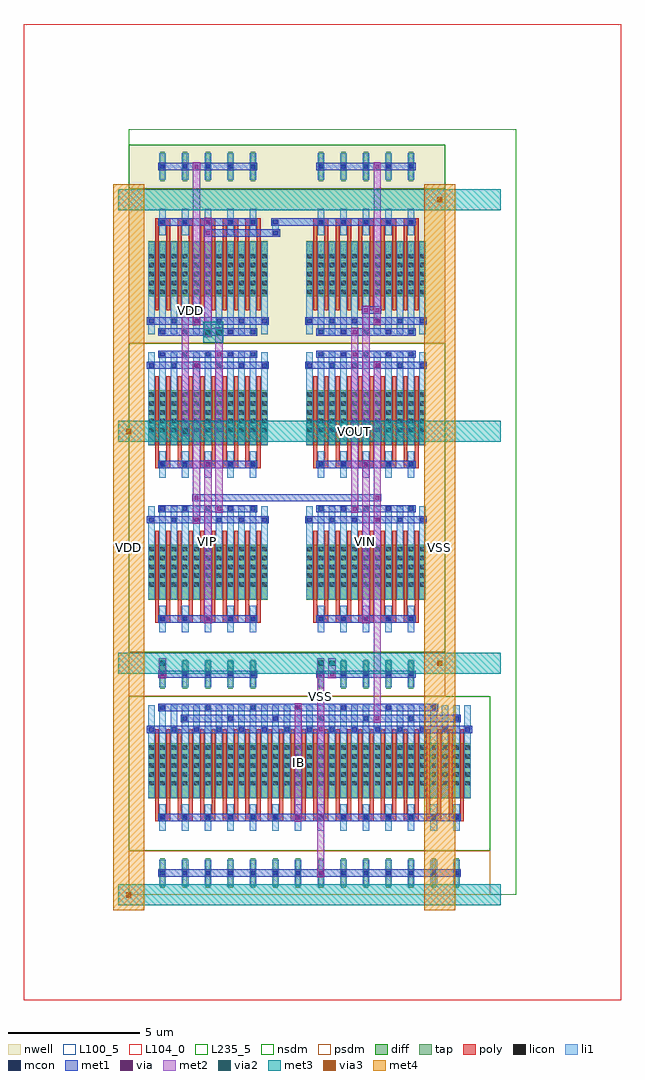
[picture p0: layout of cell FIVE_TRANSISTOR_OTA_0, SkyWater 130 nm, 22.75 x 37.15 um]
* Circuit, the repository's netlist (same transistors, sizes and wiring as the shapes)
* NGSPICE file created from FIVE_TRANSISTOR_OTA_0.ext - technology: sky130A

.subckt DCL_PMOS_S_78259359_X5_Y1_1774868955 a_200_252# w_0_0#
X0 a_200_252# a_200_252# w_0_0# w_0_0# sky130_fd_pr__pfet_01v8 ad=0.294 pd=2.38 as=0.5565 ps=4.73 w=2.1 l=0.15 M=10
.ends

.subckt NMOS_4T_1818045_X5_Y2_1774868956 a_230_357# a_200_252# a_147_357# a_241_2408#
X0 a_230_357# a_200_252# a_147_357# a_241_2408# sky130_fd_pr__nfet_01v8 ad=0.294 pd=2.38 as=0.294 ps=2.38 w=2.1 l=0.15 M=20
.ends

.subckt PMOS_S_49267959_X5_Y1_1774868957 a_230_357# a_200_252# w_0_0#
X0 a_230_357# a_200_252# w_0_0# w_0_0# sky130_fd_pr__pfet_01v8 ad=0.294 pd=2.38 as=0.5565 ps=4.73 w=2.1 l=0.15 M=10
.ends

.subckt SCM_NMOS_72619132_X7_Y1_1774868958 a_200_252# a_402_357# a_147_357#
X0 a_200_252# a_200_252# a_147_357# a_147_357# sky130_fd_pr__nfet_01v8 ad=0.294 pd=2.38 as=0.294 ps=2.38 w=2.1 l=0.15 M=14
X1 a_147_357# a_200_252# a_402_357# a_147_357# sky130_fd_pr__nfet_01v8 ad=0.294 pd=2.38 as=0.294 ps=2.38 w=2.1 l=0.15 M=14
.ends

.subckt FIVE_TRANSISTOR_OTA_0 IB VOUT VIP VIN VSS VDD
XDCL_PMOS_S_78259359_X5_Y1_1774868955_0 m2_574_4247# VDD DCL_PMOS_S_78259359_X5_Y1_1774868955
XNMOS_4T_1818045_X5_Y2_1774868956_0 VOUT VIN m1_484_2996# VSS NMOS_4T_1818045_X5_Y2_1774868956
XNMOS_4T_1818045_X5_Y2_1774868956_1 m2_574_4247# VIP m1_484_2996# VSS NMOS_4T_1818045_X5_Y2_1774868956
XPMOS_S_49267959_X5_Y1_1774868957_0 VOUT m2_574_4247# VDD PMOS_S_49267959_X5_Y1_1774868957
XSCM_NMOS_72619132_X7_Y1_1774868958_0 IB m1_484_2996# VSS SCM_NMOS_72619132_X7_Y1_1774868958
.ends

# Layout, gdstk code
from math import pi, radians
import gdstk
lib = gdstk.Library(unit=1e-6, precision=1e-09)
def R(c, l, rs):  # rectangles x0, y0, x1, y1
    for r in rs: c.add(gdstk.rectangle(r[:2], r[2:], *l))
def A(c, l, x, y, w, h, nx, ny, dx, dy):  # array of equal rectangles
    R(c, l, [(x+i*dx, y+j*dy, x+i*dx+w, y+j*dy+h) for i in range(nx) for j in range(ny)])
def P(c, l, *ps):  # polygons
    for p in ps: c.add(gdstk.Polygon(p, *l))
nwell = (64, 20)
diff = (65, 20)
tap = (65, 44)
poly = (66, 20)
licon = (66, 44)
li1 = (67, 20)
mcon = (67, 44)
met1 = (68, 20)
via = (68, 44)
met2 = (69, 20)
via2 = (69, 44)
met3 = (70, 20)
via3 = (70, 44)
met4 = (71, 20)
nsdm = (93, 44)
psdm = (94, 20)
L100_5 = (100, 5)
L104_0 = (104, 0)
L235_5 = (235, 5)

scm_nmos_72619132_x7_y1_ = lib.new_cell('SCM_NMOS_72619132_X7_Y1_1774868958')
R(scm_nmos_72619132_x7_y1_, diff, [(0.735,1.785,13.025,3.885)])
A(scm_nmos_72619132_x7_y1_, tap, 1.205, 6.16, 0.17, 1.12, 14, 1, 0.86, 0)
A(scm_nmos_72619132_x7_y1_, poly, 1, 1.26, 0.15, 3.36, 28, 1, 0.43, 0)
A(scm_nmos_72619132_x7_y1_, poly, 1, 4.485, 0.58, 0.27, 14, 1, 0.86, 0)
A(scm_nmos_72619132_x7_y1_, licon, 0.775, 1.865, 0.17, 0.17, 3, 5, 0.43, 0.34)
A(scm_nmos_72619132_x7_y1_, licon, 1.635, 1.865, 0.17, 0.17, 3, 5, 0.43, 0.34)
A(scm_nmos_72619132_x7_y1_, licon, 2.495, 1.865, 0.17, 0.17, 3, 5, 0.43, 0.34)
A(scm_nmos_72619132_x7_y1_, licon, 3.355, 1.865, 0.17, 0.17, 3, 5, 0.43, 0.34)
A(scm_nmos_72619132_x7_y1_, licon, 4.215, 1.865, 0.17, 0.17, 3, 5, 0.43, 0.34)
A(scm_nmos_72619132_x7_y1_, licon, 5.075, 1.865, 0.17, 0.17, 3, 5, 0.43, 0.34)
A(scm_nmos_72619132_x7_y1_, licon, 5.935, 1.865, 0.17, 0.17, 3, 5, 0.43, 0.34)
A(scm_nmos_72619132_x7_y1_, licon, 6.795, 1.865, 0.17, 0.17, 3, 5, 0.43, 0.34)
A(scm_nmos_72619132_x7_y1_, licon, 7.655, 1.865, 0.17, 0.17, 3, 5, 0.43, 0.34)
A(scm_nmos_72619132_x7_y1_, licon, 8.515, 1.865, 0.17, 0.17, 3, 5, 0.43, 0.34)
A(scm_nmos_72619132_x7_y1_, licon, 9.375, 1.865, 0.17, 0.17, 3, 5, 0.43, 0.34)
A(scm_nmos_72619132_x7_y1_, licon, 10.235, 1.865, 0.17, 0.17, 3, 5, 0.43, 0.34)
A(scm_nmos_72619132_x7_y1_, licon, 11.095, 1.865, 0.17, 0.17, 3, 5, 0.43, 0.34)
A(scm_nmos_72619132_x7_y1_, licon, 11.955, 1.865, 0.17, 0.17, 3, 5, 0.43, 0.34)
A(scm_nmos_72619132_x7_y1_, licon, 1.205, 4.535, 0.17, 0.17, 14, 2, 0.86, 2.1)
A(scm_nmos_72619132_x7_y1_, li1, 0.735, 0.335, 0.25, 3.53, 29, 1, 0.43, 0)
A(scm_nmos_72619132_x7_y1_, li1, 1.165, 4.115, 0.25, 1.01, 14, 2, 0.86, 2.1)
A(scm_nmos_72619132_x7_y1_, mcon, 1.205, 0.335, 0.17, 0.17, 7, 1, 1.72, 0)
A(scm_nmos_72619132_x7_y1_, mcon, 2.065, 0.755, 0.17, 0.17, 7, 1, 1.72, 0)
A(scm_nmos_72619132_x7_y1_, mcon, 0.775, 1.175, 0.17, 0.17, 15, 1, 0.86, 0)
A(scm_nmos_72619132_x7_y1_, mcon, 1.205, 4.535, 0.17, 0.17, 14, 2, 0.86, 2.1)
R(scm_nmos_72619132_x7_y1_, met1, [(1.12,0.28,11.78,0.56), (1.98,0.7,12.64,0.98), (0.69,1.12,13.07,1.4), (1.12,4.48,12.64,4.76), (1.12,6.58,12.64,6.86)])
R(scm_nmos_72619132_x7_y1_, via, [(6.375,0.345,6.525,0.495), (7.235,1.185,7.385,1.335), (6.375,4.545,6.525,4.695), (7.235,6.645,7.385,6.795)])
R(scm_nmos_72619132_x7_y1_, met2, [(6.31,0.26,6.59,4.78), (7.17,1.1,7.45,6.88)])
R(scm_nmos_72619132_x7_y1_, nsdm, [(0,0,13.76,5.88)])
R(scm_nmos_72619132_x7_y1_, psdm, [(0,5.88,13.76,7.56)])
R(scm_nmos_72619132_x7_y1_, L100_5, [(0,0,13.76,7.56)])

dcl_pmos_s_78259359_x5_y = lib.new_cell('DCL_PMOS_S_78259359_X5_Y1_1774868955')
R(dcl_pmos_s_78259359_x5_y, nwell, [(0,0,6.02,7.56)])
R(dcl_pmos_s_78259359_x5_y, diff, [(0.735,1.785,5.285,3.885)])
A(dcl_pmos_s_78259359_x5_y, tap, 1.205, 6.16, 0.17, 1.12, 5, 1, 0.86, 0)
A(dcl_pmos_s_78259359_x5_y, poly, 1, 1.26, 0.15, 3.36, 10, 1, 0.43, 0)
A(dcl_pmos_s_78259359_x5_y, poly, 1, 4.485, 0.58, 0.27, 5, 1, 0.86, 0)
A(dcl_pmos_s_78259359_x5_y, licon, 0.775, 1.865, 0.17, 0.17, 3, 5, 0.43, 0.34)
A(dcl_pmos_s_78259359_x5_y, licon, 1.635, 1.865, 0.17, 0.17, 3, 5, 0.43, 0.34)
A(dcl_pmos_s_78259359_x5_y, licon, 2.495, 1.865, 0.17, 0.17, 3, 5, 0.43, 0.34)
A(dcl_pmos_s_78259359_x5_y, licon, 3.355, 1.865, 0.17, 0.17, 3, 5, 0.43, 0.34)
A(dcl_pmos_s_78259359_x5_y, licon, 4.215, 1.865, 0.17, 0.17, 3, 5, 0.43, 0.34)
A(dcl_pmos_s_78259359_x5_y, licon, 1.205, 4.535, 0.17, 0.17, 5, 2, 0.86, 2.1)
A(dcl_pmos_s_78259359_x5_y, li1, 0.735, 0.335, 0.25, 3.53, 11, 1, 0.43, 0)
A(dcl_pmos_s_78259359_x5_y, li1, 1.165, 4.115, 0.25, 1.01, 5, 2, 0.86, 2.1)
A(dcl_pmos_s_78259359_x5_y, mcon, 1.205, 0.335, 0.17, 0.17, 5, 2, 0.86, 4.2)
A(dcl_pmos_s_78259359_x5_y, mcon, 0.775, 0.755, 0.17, 0.17, 6, 1, 0.86, 0)
A(dcl_pmos_s_78259359_x5_y, mcon, 1.205, 6.635, 0.17, 0.17, 5, 1, 0.86, 0)
R(dcl_pmos_s_78259359_x5_y, met1, [(1.12,0.28,4.9,0.56), (0.69,0.7,5.33,0.98), (1.12,4.48,4.9,4.76), (1.12,6.58,4.9,6.86)])
R(dcl_pmos_s_78259359_x5_y, via, [(2.935,0.345,3.085,0.495), (3.365,0.765,3.515,0.915), (2.935,4.545,3.085,4.695), (3.365,6.645,3.515,6.795)])
R(dcl_pmos_s_78259359_x5_y, met2, [(2.87,0.26,3.15,4.78), (3.3,0.68,3.58,6.88)])
R(dcl_pmos_s_78259359_x5_y, nsdm, [(0,5.88,6.02,7.56)])
R(dcl_pmos_s_78259359_x5_y, psdm, [(0,0,6.02,5.88)])
R(dcl_pmos_s_78259359_x5_y, L100_5, [(0,0,6.02,7.56)])

pmos_s_49267959_x5_y1_17 = lib.new_cell('PMOS_S_49267959_X5_Y1_1774868957')
R(pmos_s_49267959_x5_y1_17, nwell, [(0,0,6.02,7.56)])
R(pmos_s_49267959_x5_y1_17, diff, [(0.735,1.785,5.285,3.885)])
A(pmos_s_49267959_x5_y1_17, tap, 1.205, 6.16, 0.17, 1.12, 5, 1, 0.86, 0)
A(pmos_s_49267959_x5_y1_17, poly, 1, 1.26, 0.15, 3.36, 10, 1, 0.43, 0)
A(pmos_s_49267959_x5_y1_17, poly, 1, 4.485, 0.58, 0.27, 5, 1, 0.86, 0)
A(pmos_s_49267959_x5_y1_17, licon, 0.775, 1.865, 0.17, 0.17, 3, 5, 0.43, 0.34)
A(pmos_s_49267959_x5_y1_17, licon, 1.635, 1.865, 0.17, 0.17, 3, 5, 0.43, 0.34)
A(pmos_s_49267959_x5_y1_17, licon, 2.495, 1.865, 0.17, 0.17, 3, 5, 0.43, 0.34)
A(pmos_s_49267959_x5_y1_17, licon, 3.355, 1.865, 0.17, 0.17, 3, 5, 0.43, 0.34)
A(pmos_s_49267959_x5_y1_17, licon, 4.215, 1.865, 0.17, 0.17, 3, 5, 0.43, 0.34)
A(pmos_s_49267959_x5_y1_17, licon, 1.205, 4.535, 0.17, 0.17, 5, 2, 0.86, 2.1)
A(pmos_s_49267959_x5_y1_17, li1, 0.735, 0.335, 0.25, 3.53, 11, 1, 0.43, 0)
A(pmos_s_49267959_x5_y1_17, li1, 1.165, 4.115, 0.25, 1.01, 5, 2, 0.86, 2.1)
A(pmos_s_49267959_x5_y1_17, mcon, 1.205, 0.335, 0.17, 0.17, 5, 2, 0.86, 4.2)
A(pmos_s_49267959_x5_y1_17, mcon, 0.775, 0.755, 0.17, 0.17, 6, 1, 0.86, 0)
A(pmos_s_49267959_x5_y1_17, mcon, 1.205, 6.635, 0.17, 0.17, 5, 1, 0.86, 0)
R(pmos_s_49267959_x5_y1_17, met1, [(1.12,0.28,4.9,0.56), (0.69,0.7,5.33,0.98), (1.12,4.48,4.9,4.76), (1.12,6.58,4.9,6.86)])
R(pmos_s_49267959_x5_y1_17, via, [(3.365,0.765,3.515,0.915), (3.365,6.645,3.515,6.795)])
R(pmos_s_49267959_x5_y1_17, met2, [(3.3,0.68,3.58,6.88)])
R(pmos_s_49267959_x5_y1_17, nsdm, [(0,5.88,6.02,7.56)])
R(pmos_s_49267959_x5_y1_17, psdm, [(0,0,6.02,5.88)])
R(pmos_s_49267959_x5_y1_17, L100_5, [(0,0,6.02,7.56)])

nmos_4t_1818045_x5_y2_17 = lib.new_cell('NMOS_4T_1818045_X5_Y2_1774868956')
R(nmos_4t_1818045_x5_y2_17, diff, [(0.735,1.785,5.285,3.885), (0.735,7.665,5.285,9.765)])
A(nmos_4t_1818045_x5_y2_17, tap, 1.205, 12.04, 0.17, 1.12, 5, 1, 0.86, 0)
A(nmos_4t_1818045_x5_y2_17, poly, 1, 1.26, 0.15, 3.36, 10, 2, 0.43, 5.88)
A(nmos_4t_1818045_x5_y2_17, poly, 1, 4.485, 0.58, 0.27, 5, 2, 0.86, 5.88)
A(nmos_4t_1818045_x5_y2_17, licon, 0.775, 1.865, 0.17, 0.17, 3, 5, 0.43, 0.34)
A(nmos_4t_1818045_x5_y2_17, licon, 1.635, 1.865, 0.17, 0.17, 3, 5, 0.43, 0.34)
A(nmos_4t_1818045_x5_y2_17, licon, 2.495, 1.865, 0.17, 0.17, 3, 5, 0.43, 0.34)
A(nmos_4t_1818045_x5_y2_17, licon, 3.355, 1.865, 0.17, 0.17, 3, 5, 0.43, 0.34)
A(nmos_4t_1818045_x5_y2_17, licon, 4.215, 1.865, 0.17, 0.17, 3, 5, 0.43, 0.34)
A(nmos_4t_1818045_x5_y2_17, licon, 1.205, 4.535, 0.17, 0.17, 5, 2, 0.86, 5.88)
A(nmos_4t_1818045_x5_y2_17, licon, 0.775, 7.745, 0.17, 0.17, 3, 5, 0.43, 0.34)
A(nmos_4t_1818045_x5_y2_17, licon, 1.635, 7.745, 0.17, 0.17, 3, 5, 0.43, 0.34)
A(nmos_4t_1818045_x5_y2_17, licon, 2.495, 7.745, 0.17, 0.17, 3, 5, 0.43, 0.34)
A(nmos_4t_1818045_x5_y2_17, licon, 3.355, 7.745, 0.17, 0.17, 3, 5, 0.43, 0.34)
A(nmos_4t_1818045_x5_y2_17, licon, 4.215, 7.745, 0.17, 0.17, 3, 5, 0.43, 0.34)
R(nmos_4t_1818045_x5_y2_17, licon, [(1.205,12.515,1.375,12.685), (1.205,12.515,1.375,12.685), (2.065,12.515,2.235,12.685), (2.065,12.515,2.235,12.685), (2.925,12.515,3.095,12.685), (2.925,12.515,3.095,12.685), (3.785,12.515,3.955,12.685), (3.785,12.515,3.955,12.685), (4.645,12.515,4.815,12.685), (4.645,12.515,4.815,12.685)])
A(nmos_4t_1818045_x5_y2_17, li1, 0.735, 0.335, 0.25, 3.53, 11, 2, 0.43, 5.88)
A(nmos_4t_1818045_x5_y2_17, li1, 1.165, 4.115, 0.25, 1.01, 5, 2, 0.86, 5.88)
A(nmos_4t_1818045_x5_y2_17, li1, 1.165, 12.095, 0.25, 1.01, 5, 1, 0.86, 0)
A(nmos_4t_1818045_x5_y2_17, mcon, 1.205, 0.335, 0.17, 0.17, 5, 2, 0.86, 4.2)
A(nmos_4t_1818045_x5_y2_17, mcon, 0.775, 0.755, 0.17, 0.17, 6, 2, 0.86, 5.88)
A(nmos_4t_1818045_x5_y2_17, mcon, 1.205, 6.215, 0.17, 0.17, 5, 2, 0.86, 4.2)
A(nmos_4t_1818045_x5_y2_17, mcon, 1.205, 12.515, 0.17, 0.17, 5, 1, 0.86, 0)
R(nmos_4t_1818045_x5_y2_17, met1, [(1.12,0.28,4.9,0.56), (0.69,0.7,5.33,0.98), (1.12,4.48,4.9,4.76), (1.12,6.16,4.9,6.44), (0.69,6.58,5.33,6.86), (1.12,10.36,4.9,10.64), (1.12,12.46,4.9,12.74)])
R(nmos_4t_1818045_x5_y2_17, via, [(2.505,0.345,2.655,0.495), (3.365,0.765,3.515,0.915), (2.935,4.545,3.085,4.695), (2.505,6.225,2.655,6.375), (3.365,6.645,3.515,6.795), (2.935,10.425,3.085,10.575)])
R(nmos_4t_1818045_x5_y2_17, met2, [(2.44,0.26,2.72,6.46), (3.3,0.68,3.58,6.88), (2.87,4.46,3.15,10.66)])
R(nmos_4t_1818045_x5_y2_17, nsdm, [(0,0,6.02,11.76)])
R(nmos_4t_1818045_x5_y2_17, psdm, [(0,11.76,6.02,13.44)])
R(nmos_4t_1818045_x5_y2_17, L100_5, [(0,0,6.02,13.44)])

five_transistor_ota_0 = lib.new_cell('FIVE_TRANSISTOR_OTA_0')
R(five_transistor_ota_0, li1, [(5.465,25.115,5.715,25.285), (5.465,25.115,5.715,25.285), (5.465,25.2,5.715,25.62), (5.465,25.535,5.715,25.705), (5.465,25.535,5.715,25.705)])
R(five_transistor_ota_0, mcon, [(5.505,25.115,5.675,25.285), (5.505,25.115,5.675,25.285), (5.505,25.535,5.675,25.705), (5.505,25.535,5.675,25.705)])
R(five_transistor_ota_0, met1, [(9.3,6.58,9.62,6.86), (9.3,6.58,9.62,6.86), (9.3,6.58,9.62,6.86), (9.3,6.58,9.62,6.86), (1.13,8.26,1.45,8.54), (1.13,8.26,1.45,8.54), (1.13,8.26,1.45,8.54), (7.58,8.26,7.9,8.54), (7.58,8.26,7.9,8.54), (2.42,14.98,2.74,15.26), (2.42,14.98,2.74,15.26), (2.58,14.98,9.46,15.26), (9.3,14.98,9.62,15.26), (9.3,14.98,9.62,15.26), (8.44,21.28,8.76,21.56), (8.44,21.28,8.76,21.56), (1.99,22.12,2.31,22.4), (1.99,22.12,2.31,22.4), (1.99,22.12,2.31,22.4), (2.15,22.12,2.58,22.4), (2.42,22.12,2.74,22.4), (2.42,22.12,2.74,22.4), (2.42,22.12,2.74,22.4), (8.87,22.12,9.19,22.4), (8.87,22.12,9.19,22.4), (9.03,22.12,9.46,22.4), (9.3,22.12,9.62,22.4), (9.3,22.12,9.62,22.4), (2.85,25.06,3.17,25.34), (2.85,25.06,3.17,25.34), (3.01,25.06,5.59,25.34), (5.42,25.06,5.76,25.34), (5.42,25.06,5.76,25.34), (5.42,25.48,5.76,25.76), (5.42,25.48,5.76,25.76), (5.59,25.48,7.31,25.76)])
P(five_transistor_ota_0, met1, [(0,0),(0,0),(0,0),(0,0)],
  [(0,0),(0,0),(0,0),(0,0)],
  [(0,0),(0,0),(0,0),(0,0)],
  [(0,0),(0,0),(0,0),(0,0)],
  [(0,0),(0,0),(0,0),(0,0)])
R(five_transistor_ota_0, via, [(9.385,6.645,9.535,6.795), (9.385,6.645,9.535,6.795), (9.385,6.645,9.535,6.795), (9.385,6.645,9.535,6.795), (1.215,8.325,1.365,8.475), (1.215,8.325,1.365,8.475), (1.215,8.325,1.365,8.475), (7.665,8.325,7.815,8.475), (7.665,8.325,7.815,8.475), (2.505,15.045,2.655,15.195), (2.505,15.045,2.655,15.195), (9.385,15.045,9.535,15.195), (9.385,15.045,9.535,15.195), (8.525,21.345,8.675,21.495), (8.525,21.345,8.675,21.495), (2.075,22.185,2.225,22.335), (2.075,22.185,2.225,22.335), (2.075,22.185,2.225,22.335), (2.505,22.185,2.655,22.335), (2.505,22.185,2.655,22.335), (2.505,22.185,2.655,22.335), (8.955,22.185,9.105,22.335), (8.955,22.185,9.105,22.335), (9.385,22.185,9.535,22.335), (9.385,22.185,9.535,22.335), (2.935,25.125,3.085,25.275), (2.935,25.125,3.085,25.275)])
R(five_transistor_ota_0, met2, [(7.17,6.3,7.45,8.82), (9.32,6.56,9.6,6.88), (9.32,6.56,9.6,6.88), (9.32,6.56,9.6,6.88), (9.32,6.56,9.6,6.88), (9.32,6.72,9.6,14.28), (1.15,8.24,1.43,8.56), (1.15,8.24,1.43,8.56), (1.15,8.24,1.43,8.56), (7.6,8.24,7.88,8.56), (7.6,8.24,7.88,8.56), (1.15,8.4,1.43,8.82), (7.6,8.4,7.88,8.82), (1.15,8.635,1.43,9.005), (1.15,8.635,1.43,9.005), (1.15,8.635,1.43,9.005), (7.17,8.635,7.45,9.005), (7.17,8.635,7.45,9.005), (7.17,8.635,7.45,9.005), (7.17,8.635,7.45,9.005), (7.6,8.635,7.88,9.005), (7.6,8.635,7.88,9.005), (2.44,14.96,2.72,15.28), (2.44,14.96,2.72,15.28), (9.32,14.96,9.6,15.28), (9.32,14.96,9.6,15.28), (2.01,17.455,2.29,17.825), (2.01,17.455,2.29,17.825), (2.01,17.455,2.29,17.825), (8.89,17.455,9.17,17.825), (8.89,17.455,9.17,17.825), (2.01,17.64,2.29,22.26), (8.89,17.64,9.17,22.26), (3.3,20.58,3.58,21.42), (8.46,20.58,8.74,21.42), (2.87,21.235,3.15,21.605), (2.87,21.235,3.15,21.605), (2.87,21.235,3.15,21.605), (2.87,21.235,3.15,21.605), (3.3,21.235,3.58,21.605), (3.3,21.235,3.58,21.605), (3.3,21.235,3.58,21.605), (3.3,21.235,3.58,21.605), (8.46,21.26,8.74,21.58), (8.46,21.26,8.74,21.58), (2.01,22.1,2.29,22.42), (2.01,22.1,2.29,22.42), (2.01,22.1,2.29,22.42), (2.44,22.1,2.72,22.42), (2.44,22.1,2.72,22.42), (2.44,22.1,2.72,22.42), (8.89,22.1,9.17,22.42), (8.89,22.1,9.17,22.42), (9.32,22.1,9.6,22.42), (9.32,22.1,9.6,22.42), (2.87,25.04,3.15,25.36), (2.87,25.04,3.15,25.36)])
P(five_transistor_ota_0, met2, [(0,0),(0,0),(0,0),(0,0)],
  [(0,0),(0,0),(0,0),(0,0)],
  [(0,0),(0,0),(0,0),(0,0)],
  [(0,0),(0,0),(0,0),(0,0)],
  [(0,0),(0,0),(0,0),(0,0)],
  [(0,0),(0,0),(0,0),(0,0)],
  [(0,0),(0,0),(0,0),(0,0)],
  [(0,0),(0,0),(0,0),(0,0)],
  [(0,0),(0,0),(0,0),(0,0)],
  [(0,0),(0,0),(0,0),(0,0)],
  [(0,0),(0,0),(0,0),(0,0)],
  [(0,0),(0,0),(0,0),(0,0)],
  [(0,0),(0,0),(0,0),(0,0)],
  [(0,0),(0,0),(0,0),(0,0)],
  [(0,0),(0,0),(0,0),(0,0)])
R(five_transistor_ota_0, via2, [(1.19,8.72,1.39,8.92), (1.19,8.72,1.39,8.92), (1.19,8.72,1.39,8.92), (7.21,8.72,7.41,8.92), (7.21,8.72,7.41,8.92), (7.21,8.72,7.41,8.92), (7.21,8.72,7.41,8.92), (7.64,8.72,7.84,8.92), (7.64,8.72,7.84,8.92), (2.05,17.54,2.25,17.74), (2.05,17.54,2.25,17.74), (2.05,17.54,2.25,17.74), (8.93,17.54,9.13,17.74), (8.93,17.54,9.13,17.74), (2.91,21.32,3.11,21.52), (2.91,21.32,3.11,21.52), (2.91,21.32,3.11,21.52), (2.91,21.32,3.11,21.52), (3.34,21.32,3.54,21.52), (3.34,21.32,3.54,21.52), (3.34,21.32,3.54,21.52), (3.34,21.32,3.54,21.52)])
A(five_transistor_ota_0, met3, -0.4, -0.4, 4.24, 0.8, 3, 4, 3.44, 8.82)
A(five_transistor_ota_0, met3, 9.92, -0.4, 2.32, 0.8, 1, 4, 0, 8.82)
A(five_transistor_ota_0, met3, 11.44, -0.4, 2.72, 0.8, 1, 4, 0, 8.82)
R(five_transistor_ota_0, met3, [(-0.165,-0.4,0.165,0.4), (1.125,8.42,1.455,9.22), (1.125,8.42,1.455,9.22), (1.125,8.42,1.455,9.22), (7.145,8.42,7.475,9.22), (7.145,8.42,7.475,9.22), (7.145,8.42,7.475,9.22), (7.145,8.42,7.475,9.22), (7.575,8.42,7.905,9.22), (7.575,8.42,7.905,9.22), (11.675,8.42,12.005,9.22), (-0.165,17.24,0.165,18.04), (1.985,17.24,2.315,18.04), (1.985,17.24,2.315,18.04), (1.985,17.24,2.315,18.04), (8.865,17.24,9.195,18.04), (8.865,17.24,9.195,18.04), (2.845,21.02,3.175,21.82), (2.845,21.02,3.175,21.82), (2.845,21.02,3.175,21.82), (2.845,21.02,3.175,21.82), (3.01,21.02,3.44,21.82), (3.275,21.02,3.605,21.82), (3.275,21.02,3.605,21.82), (3.275,21.02,3.605,21.82), (3.275,21.02,3.605,21.82), (11.675,26.06,12.005,26.86)])
R(five_transistor_ota_0, via3, [(-0.1,-0.1,0.1,0.1), (11.74,8.72,11.94,8.92), (-0.1,17.54,0.1,17.74), (11.74,26.36,11.94,26.56)])
A(five_transistor_ota_0, met4, -0.59, -0.59, 1.18, 10, 1, 3, 0, 8.82)
A(five_transistor_ota_0, met4, 11.25, -0.59, 1.18, 10, 1, 3, 0, 8.82)
R(five_transistor_ota_0, met4, [(-0.59,-0.165,0.59,0.165), (11.25,8.655,12.43,8.985), (-0.59,17.475,0.59,17.805), (11.25,26.295,12.43,26.625)])
R(five_transistor_ota_0, L104_0, [(-4,-4,18.75,33.15)])
R(five_transistor_ota_0, L235_5, [(0,0,14.75,29.15)])
five_transistor_ota_0.add(gdstk.Reference(scm_nmos_72619132_x7_y1_, (0,7.56), x_reflection=True))
five_transistor_ota_0.add(gdstk.Reference(dcl_pmos_s_78259359_x5_y, (6.02,21), rotation=pi, x_reflection=True))
five_transistor_ota_0.add(gdstk.Reference(pmos_s_49267959_x5_y1_17, (6.02,21)))
five_transistor_ota_0.add(gdstk.Reference(nmos_4t_1818045_x5_y2_17, (6.02,21), rotation=pi))
five_transistor_ota_0.add(gdstk.Reference(nmos_4t_1818045_x5_y2_17, (6.02,21), x_reflection=True))
five_transistor_ota_0.add(gdstk.Label('IB', (6.45,5.04), layer=69, texttype=5))
five_transistor_ota_0.add(gdstk.Label('VOUT', (8.6,17.64), layer=69, texttype=5))
five_transistor_ota_0.add(gdstk.Label('VIP', (3.01,13.44), layer=69, texttype=5))
five_transistor_ota_0.add(gdstk.Label('VIN', (9.03,13.44), layer=69, texttype=5))
five_transistor_ota_0.add(gdstk.Label('VSS', (7.31,7.56), layer=69, texttype=5))
five_transistor_ota_0.add(gdstk.Label('VSS', (11.84,13.23), layer=71, texttype=5))
five_transistor_ota_0.add(gdstk.Label('VSS', (11.84,13.23), layer=71, texttype=5))
five_transistor_ota_0.add(gdstk.Label('VSS', (11.84,13.23), layer=71, texttype=5))
five_transistor_ota_0.add(gdstk.Label('VSS', (11.84,13.23), layer=71, texttype=5))
five_transistor_ota_0.add(gdstk.Label('VSS', (11.84,13.23), layer=71, texttype=5))
five_transistor_ota_0.add(gdstk.Label('VSS', (11.84,13.23), layer=71, texttype=5))
five_transistor_ota_0.add(gdstk.Label('VSS', (11.84,13.23), layer=71, texttype=5))
five_transistor_ota_0.add(gdstk.Label('VSS', (11.84,13.23), layer=71, texttype=5))
five_transistor_ota_0.add(gdstk.Label('VDD', (0,13.23), layer=71, texttype=5))
five_transistor_ota_0.add(gdstk.Label('VDD', (2.365,22.26), layer=68, texttype=5))
five_transistor_ota_0.add(gdstk.Label('VDD', (0,13.23), layer=71, texttype=5))
five_transistor_ota_0.add(gdstk.Label('VDD', (0,13.23), layer=71, texttype=5))
five_transistor_ota_0.add(gdstk.Label('VDD', (0,13.23), layer=71, texttype=5))
five_transistor_ota_0.add(gdstk.Label('VDD', (0,13.23), layer=71, texttype=5))
five_transistor_ota_0.add(gdstk.Label('VDD', (0,13.23), layer=71, texttype=5))
five_transistor_ota_0.add(gdstk.Label('VDD', (0,13.23), layer=71, texttype=5))
five_transistor_ota_0.add(gdstk.Label('VDD', (0,13.23), layer=71, texttype=5))

lib.write_gds('FIVE_TRANSISTOR_OTA_0.gds')
